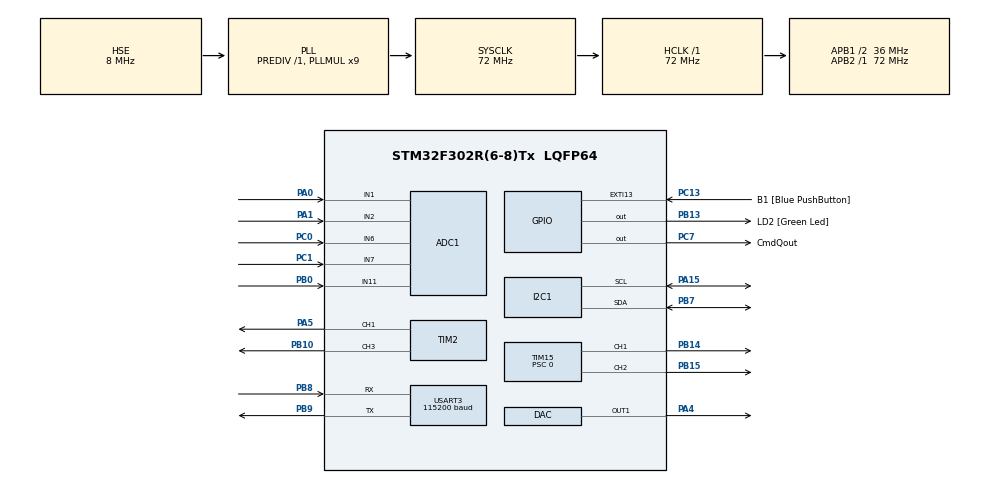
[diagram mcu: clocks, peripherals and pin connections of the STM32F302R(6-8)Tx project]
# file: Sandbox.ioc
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ADC1.Channel-0\#ChannelRegularConversion=ADC_CHANNEL_1
ADC1.Channel-3\#ChannelRegularConversion=ADC_CHANNEL_11
ADC1.Channel-4\#ChannelRegularConversion=ADC_CHANNEL_6
ADC1.Channel-5\#ChannelRegularConversion=ADC_CHANNEL_7
ADC1.ContinuousConvMode=ENABLE
ADC1.DMAContinuousRequests=ENABLE
ADC1.EOCSelection=ADC_EOC_SINGLE_CONV
ADC1.EnableInjectedConversion=DISABLE
ADC1.NbrOfConversion=4
ADC1.NbrOfConversionFlag=1
ADC1.Offset-0\#ChannelRegularConversion=0
ADC1.Offset-3\#ChannelRegularConversion=0
ADC1.Offset-4\#ChannelRegularConversion=0
ADC1.Offset-5\#ChannelRegularConversion=0
ADC1.OffsetNumber-0\#ChannelRegularConversion=ADC_OFFSET_NONE
ADC1.OffsetNumber-3\#ChannelRegularConversion=ADC_OFFSET_NONE
ADC1.OffsetNumber-4\#ChannelRegularConversion=ADC_OFFSET_NONE
ADC1.OffsetNumber-5\#ChannelRegularConversion=ADC_OFFSET_NONE
ADC1.Rank-0\#ChannelRegularConversion=1
ADC1.Rank-3\#ChannelRegularConversion=2
ADC1.Rank-4\#ChannelRegularConversion=3
ADC1.Rank-5\#ChannelRegularConversion=4
ADC1.SamplingTime-0\#ChannelRegularConversion=ADC_SAMPLETIME_7CYCLES_5
ADC1.SamplingTime-3\#ChannelRegularConversion=ADC_SAMPLETIME_7CYCLES_5
ADC1.SamplingTime-4\#ChannelRegularConversion=ADC_SAMPLETIME_7CYCLES_5
ADC1.SamplingTime-5\#ChannelRegularConversion=ADC_SAMPLETIME_7CYCLES_5
ADC1.SequencerNbRanks=1
ADC1.SubFamily=STM32F302x8
ADC1.master=1
DAC.DAC_Trigger=DAC_TRIGGER_NONE
Dma.ADC1.0.Direction=DMA_PERIPH_TO_MEMORY
Dma.ADC1.0.Instance=DMA1_Channel1
Dma.ADC1.0.MemDataAlignment=DMA_MDATAALIGN_WORD
Dma.ADC1.0.MemInc=DMA_MINC_ENABLE
Dma.ADC1.0.Mode=DMA_CIRCULAR
Dma.ADC1.0.PeriphDataAlignment=DMA_PDATAALIGN_HALFWORD
Dma.ADC1.0.PeriphInc=DMA_PINC_DISABLE
Dma.ADC1.0.Priority=DMA_PRIORITY_HIGH
Dma.Request0=ADC1
Dma.Request1=USART3_TX
Dma.USART3_TX.1.Direction=DMA_MEMORY_TO_PERIPH
Dma.USART3_TX.1.Instance=DMA1_Channel2
Dma.USART3_TX.1.MemDataAlignment=DMA_MDATAALIGN_BYTE
Dma.USART3_TX.1.MemInc=DMA_MINC_ENABLE
Dma.USART3_TX.1.Mode=DMA_NORMAL
Dma.USART3_TX.1.PeriphDataAlignment=DMA_PDATAALIGN_BYTE
Dma.USART3_TX.1.PeriphInc=DMA_PINC_DISABLE
Dma.USART3_TX.1.Priority=DMA_PRIORITY_LOW
Mcu.Family=STM32F3
Mcu.Name=STM32F302R(6-8)Tx
Mcu.Package=LQFP64
Mcu.UserConstants=TIM15_PERIOD_TICKS,4800;TIM2_PERIOD_TICKS,2400
NVIC.DMA1_Channel1_IRQn=true\:0\:0\:false\:false\:true\:false\:true\:true
NVIC.DMA1_Channel2_IRQn=true\:0\:0\:false\:false\:true\:false\:true\:true
NVIC.I2C1_EV_IRQn=true\:0\:0\:false\:false\:true\:true\:true\:true
NVIC.PriorityGroup=NVIC_PRIORITYGROUP_0
NVIC.USART3_IRQn=true\:0\:0\:false\:false\:true\:true\:true\:true
PA0.Mode=IN1-Single-Ended
PA0.Signal=ADC1_IN1
PA1.Mode=IN2-Single-Ended
PA1.Signal=ADC1_IN2
PA13.GPIO_Label=TMS
PA13.Mode=Serial_Wire
PA13.Signal=SYS_JTMS-SWDIO
PA14.GPIO_Label=TCK
PA14.Mode=Serial_Wire
PA14.Signal=SYS_JTCK-SWCLK
PA15.Mode=I2C
PA15.Signal=I2C1_SCL
PA2.GPIO_Label=USART_TX
PA2.GPIO_Mode=GPIO_MODE_AF_PP
PA2.GPIO_PuPd=GPIO_NOPULL
PA2.GPIO_Speed=GPIO_SPEED_FREQ_LOW
PA2.Signal=USART2_TX
PA3.GPIO_Label=USART_RX
PA3.GPIO_Mode=GPIO_MODE_AF_PP
PA3.GPIO_PuPd=GPIO_NOPULL
PA3.GPIO_Speed=GPIO_SPEED_FREQ_LOW
PA3.Signal=USART2_RX
PA4.Signal=COMP_DAC1_group
PA5.Signal=S_TIM2_CH1_ETR
PB0.Mode=IN11-Single-Ended
PB0.Signal=ADC1_IN11
PB10.Signal=S_TIM2_CH3
PB13.GPIO_Label=LD2 [Green Led]
PB13.Signal=GPIO_Output
PB14.GPIO_PuPd=GPIO_NOPULL
PB14.GPIO_Speed=GPIO_SPEED_FREQ_HIGH
PB14.Signal=S_TIM15_CH1
PB15.Signal=S_TIM15_CH2
PB3.GPIO_Label=SWO
PB3.Mode=Trace_Asynchronous_SW
PB3.Signal=SYS_JTDO-TRACESWO
PB7.Mode=I2C
PB7.Signal=I2C1_SDA
PB8.Mode=Asynchronous
PB8.Signal=USART3_RX
PB9.Mode=Asynchronous
PB9.Signal=USART3_TX
PC0.Signal=ADCx_IN6
PC1.Signal=ADCx_IN7
PC13.GPIO_Label=B1 [Blue PushButton]
PC13.GPIO_ModeDefaultEXTI=GPIO_MODE_IT_FALLING
PC13.Signal=GPXTI13
PC14\ -\ OSC32_IN.Mode=LSE-External-Oscillator
PC14\ -\ OSC32_IN.Signal=RCC_OSC32_IN
PC15\ -\ OSC32_OUT.Mode=LSE-External-Oscillator
PC15\ -\ OSC32_OUT.Signal=RCC_OSC32_OUT
PC7.GPIO_Label=CmdQout
PC7.GPIO_PuPd=GPIO_PULLDOWN
PC7.GPIO_Speed=GPIO_SPEED_FREQ_MEDIUM
PC7.Signal=GPIO_Output
PF0-OSC_IN.Mode=HSE-External-Clock-Source
PF0-OSC_IN.Signal=RCC_OSC_IN
PF1-OSC_OUT.Signal=RCC_OSC_OUT
ProjectManager.HeapSize=0x200
ProjectManager.StackSize=0x400
ProjectManager.TargetToolchain=STM32CubeIDE
RCC.AHBFreq_Value=72000000
RCC.APB1CLKDivider=RCC_HCLK_DIV2
RCC.APB1Freq_Value=36000000
RCC.APB1TimFreq_Value=72000000
RCC.APB2Freq_Value=72000000
RCC.APB2TimFreq_Value=72000000
RCC.CortexFreq_Value=72000000
RCC.HCLKFreq_Value=72000000
RCC.HSE_VALUE=8000000
RCC.HSI_VALUE=8000000
RCC.PLLM=8
RCC.PLLMUL=RCC_PLL_MUL9
RCC.PLLN=336
RCC.PLLP=RCC_PLLP_DIV4
RCC.PLLQ=7
RCC.PLLSourceVirtual=RCC_PLLSOURCE_HSE
RCC.SYSCLKFreq_VALUE=72000000
RCC.SYSCLKSourceVirtual=RCC_SYSCLKSOURCE_PLLCLK
RCC.TIM15Selection=RCC_TIM15CLK_PLLCLK
RCC.USBFreq_Value=72000000
SH.ADCx_IN6.0=ADC1_IN6,IN6-Single-Ended
SH.ADCx_IN7.0=ADC1_IN7,IN7-Single-Ended
SH.COMP_DAC1_group.0=DAC_OUT1,DAC_OUT1
SH.S_TIM15_CH1.0=TIM15_CH1,PWM Generation1 CH1
SH.S_TIM15_CH2.0=TIM15_CH2,PWM Generation2 CH2
SH.S_TIM2_CH1_ETR.0=TIM2_CH1,PWM Generation1 CH1
SH.S_TIM2_CH3.0=TIM2_CH3,PWM Generation3 CH3
TIM15.AutoReloadPreload=TIM_AUTORELOAD_PRELOAD_ENABLE
TIM15.AutomaticOutput=TIM_AUTOMATICOUTPUT_DISABLE
TIM15.Channel-PWM\ Generation1\ CH1=TIM_CHANNEL_1
TIM15.Channel-PWM\ Generation2\ CH2=TIM_CHANNEL_2
TIM15.OC1Preload_PWM=DISABLE
TIM15.OC2Preload_PWM=DISABLE
TIM15.Period=TIM15_PERIOD_TICKS
TIM15.Prescaler=0
TIM2.AutoReloadPreload=TIM_AUTORELOAD_PRELOAD_ENABLE
TIM2.Channel-PWM\ Generation1\ CH1=TIM_CHANNEL_1
TIM2.Channel-PWM\ Generation3\ CH3=TIM_CHANNEL_3
TIM2.OC1Preload_PWM=DISABLE
TIM2.OC3Preload_PWM=DISABLE
TIM2.Period=TIM2_PERIOD_TICKS
USART3.BaudRate=115200
USART3.VirtualMode-Asynchronous=VM_ASYNC
USART3.WordLength=WORDLENGTH_8B
board=NUCLEO-F302R8

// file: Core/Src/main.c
/* USER CODE BEGIN Header */
/**
  ******************************************************************************
  * @file           : main.c
  * @brief          : Main program body
  ******************************************************************************
  * @attention
  *
  * <h2><center>&copy; Copyright (c) 2021 STMicroelectronics.
  * All rights reserved.</center></h2>
  *
  * This software component is licensed by ST under BSD 3-Clause license,
  * the "License"; You may not use this file except in compliance with the
  * License. You may obtain a copy of the License at:
  *                        opensource.org/licenses/BSD-3-Clause
  *
  ******************************************************************************
  */
/* USER CODE END Header */
#include "main.h"

/* USER CODE BEGIN Includes */
#include "threads.hpp"
/* USER CODE END Includes */

ADC_HandleTypeDef hadc1;
DMA_HandleTypeDef hdma_adc1;

DAC_HandleTypeDef hdac;

I2C_HandleTypeDef hi2c1;

TIM_HandleTypeDef htim2;
TIM_HandleTypeDef htim15;

UART_HandleTypeDef huart3;
DMA_HandleTypeDef hdma_usart3_tx;

/* USER CODE BEGIN PV */

ADC_HandleTypeDef*  p_hadc1;
DMA_HandleTypeDef*  p_hdma_adc1;
DAC_HandleTypeDef*  p_hdac;
I2C_HandleTypeDef*  p_hi2c1;
TIM_HandleTypeDef*  p_htim2;
TIM_HandleTypeDef*  p_htim15;
UART_HandleTypeDef* p_huart3;
DMA_HandleTypeDef*  p_hdma_usart3_tx;

/* USER CODE END PV */

void SystemClock_Config(void);
static void MX_GPIO_Init(void);
static void MX_ADC1_Init(void);
static void MX_USART3_UART_Init(void);
static void MX_DMA_Init(void);
static void MX_DAC_Init(void);
static void MX_I2C1_Init(void);
static void MX_TIM15_Init(void);
static void MX_TIM2_Init(void);

int main(void)
{
  /* USER CODE BEGIN 1 */

  p_hadc1           = &hadc1;
  p_hdma_adc1       = &hdma_adc1;
  p_hdac            = &hdac;
  p_hi2c1           = &hi2c1;
  p_htim2           = &htim2;
  p_htim15          = &htim15;
  p_huart3          = &huart3;
  p_hdma_usart3_tx  = &hdma_usart3_tx;

  /* USER CODE END 1 */

  /* MCU Configuration--------------------------------------------------------*/

  /* Reset of all peripherals, Initializes the Flash interface and the Systick. */
  HAL_Init();

  /* Configure the system clock */
  SystemClock_Config();

  /* USER CODE BEGIN SysInit */

  // TODO: !!! DMA to be initialised before ADC and other peripherals !!! ////////
  //MX_GPIO_Init();
  //MX_USART2_UART_Init();
  //MX_DMA_Init();
  //MX_ADC1_Init();
  //MX_USART3_UART_Init();
  //MX_DAC_Init();
  //MX_I2C1_Init();
  //MX_TIM15_Init();

  HAL_NVIC_SetPriorityGrouping(NVIC_PRIORITYGROUP_4);
  // ??? TODO: !!! Comment in MX_DMA_Init() : HAL_NVIC_EnableIRQ(DMA1_Channel1_IRQn); --> No interrupt required

  /* USER CODE END SysInit */

  /* Initialize all configured peripherals */
  MX_GPIO_Init();
  MX_DMA_Init();
  MX_ADC1_Init();
  MX_USART3_UART_Init();
  MX_DAC_Init();
  MX_I2C1_Init();
  MX_TIM15_Init();
  MX_TIM2_Init();
  /* USER CODE BEGIN 2 */

  init_threads();

  /* USER CODE END 2 */

  /* Infinite loop */
  /* USER CODE BEGIN WHILE */
  int a = 0;
  int flag = 0;

  while (1)
  {
    tick_polled();

    a++;
    if(a/500000 >= 1)
    {
        if (flag != 0)
        {
            HAL_GPIO_WritePin(LD2_GPIO_Port, LD2_Pin, GPIO_PIN_RESET);
            flag = 0;
        }
        else
        {
            HAL_GPIO_WritePin(LD2_GPIO_Port, LD2_Pin, GPIO_PIN_SET);
            flag = 1;
        }
        a = 0;
    }

    /* USER CODE END WHILE */

  }
}

void SystemClock_Config(void)
{
  RCC_OscInitTypeDef RCC_OscInitStruct = {0};
  RCC_ClkInitTypeDef RCC_ClkInitStruct = {0};
  RCC_PeriphCLKInitTypeDef PeriphClkInit = {0};

  /** Initializes the RCC Oscillators according to the specified parameters
  * in the RCC_OscInitTypeDef structure.
  */
  RCC_OscInitStruct.OscillatorType = RCC_OSCILLATORTYPE_HSI|RCC_OSCILLATORTYPE_HSE;
  RCC_OscInitStruct.HSEState = RCC_HSE_BYPASS;
  RCC_OscInitStruct.HSEPredivValue = RCC_HSE_PREDIV_DIV1;
  RCC_OscInitStruct.HSIState = RCC_HSI_ON;
  RCC_OscInitStruct.HSICalibrationValue = RCC_HSICALIBRATION_DEFAULT;
  RCC_OscInitStruct.PLL.PLLState = RCC_PLL_ON;
  RCC_OscInitStruct.PLL.PLLSource = RCC_PLLSOURCE_HSE;
  RCC_OscInitStruct.PLL.PLLMUL = RCC_PLL_MUL9;
  if (HAL_RCC_OscConfig(&RCC_OscInitStruct) != HAL_OK)
  {
    Error_Handler();
  }

  /** Initializes the CPU, AHB and APB buses clocks
  */
  RCC_ClkInitStruct.ClockType = RCC_CLOCKTYPE_HCLK|RCC_CLOCKTYPE_SYSCLK
                              |RCC_CLOCKTYPE_PCLK1|RCC_CLOCKTYPE_PCLK2;
  RCC_ClkInitStruct.SYSCLKSource = RCC_SYSCLKSOURCE_PLLCLK;
  RCC_ClkInitStruct.AHBCLKDivider = RCC_SYSCLK_DIV1;
  RCC_ClkInitStruct.APB1CLKDivider = RCC_HCLK_DIV2;
  RCC_ClkInitStruct.APB2CLKDivider = RCC_HCLK_DIV1;

  if (HAL_RCC_ClockConfig(&RCC_ClkInitStruct, FLASH_LATENCY_2) != HAL_OK)
  {
    Error_Handler();
  }
  PeriphClkInit.PeriphClockSelection = RCC_PERIPHCLK_I2C1|RCC_PERIPHCLK_TIM15
                              |RCC_PERIPHCLK_ADC1;
  PeriphClkInit.I2c1ClockSelection = RCC_I2C1CLKSOURCE_HSI;
  PeriphClkInit.Tim15ClockSelection = RCC_TIM15CLK_PLLCLK;
  PeriphClkInit.Adc1ClockSelection = RCC_ADC1PLLCLK_DIV1;

  if (HAL_RCCEx_PeriphCLKConfig(&PeriphClkInit) != HAL_OK)
  {
    Error_Handler();
  }
}

static void MX_ADC1_Init(void)
{

  ADC_ChannelConfTypeDef sConfig = {0};

  /** Common config
  */
  hadc1.Instance = ADC1;
  hadc1.Init.ClockPrescaler = ADC_CLOCK_ASYNC_DIV1;
  hadc1.Init.Resolution = ADC_RESOLUTION_12B;
  hadc1.Init.ScanConvMode = ADC_SCAN_ENABLE;
  hadc1.Init.ContinuousConvMode = ENABLE;
  hadc1.Init.DiscontinuousConvMode = DISABLE;
  hadc1.Init.ExternalTrigConvEdge = ADC_EXTERNALTRIGCONVEDGE_NONE;
  hadc1.Init.ExternalTrigConv = ADC_SOFTWARE_START;
  hadc1.Init.DataAlign = ADC_DATAALIGN_RIGHT;
  hadc1.Init.NbrOfConversion = 4;
  hadc1.Init.DMAContinuousRequests = ENABLE;
  hadc1.Init.EOCSelection = ADC_EOC_SINGLE_CONV;
  hadc1.Init.LowPowerAutoWait = DISABLE;
  hadc1.Init.Overrun = ADC_OVR_DATA_OVERWRITTEN;
  //if (HAL_ADC_Init(&hadc1) != HAL_OK)
  //{
  //  Error_Handler();
  //}

  /** Configure Regular Channel
  */
  sConfig.Channel = ADC_CHANNEL_1;
  sConfig.Rank = ADC_REGULAR_RANK_1;
  sConfig.SingleDiff = ADC_SINGLE_ENDED;
  sConfig.SamplingTime = ADC_SAMPLETIME_7CYCLES_5;
  sConfig.OffsetNumber = ADC_OFFSET_NONE;
  sConfig.Offset = 0;
  //if (HAL_ADC_ConfigChannel(&hadc1, &sConfig) != HAL_OK)
  //{
  //  Error_Handler();
  //}

  /** Configure Regular Channel
  */
  sConfig.Channel = ADC_CHANNEL_11;
  sConfig.Rank = ADC_REGULAR_RANK_2;
  //if (HAL_ADC_ConfigChannel(&hadc1, &sConfig) != HAL_OK)
  //{
  //  Error_Handler();
  //}

  /** Configure Regular Channel
  */
  sConfig.Channel = ADC_CHANNEL_6;
  sConfig.Rank = ADC_REGULAR_RANK_3;
  //if (HAL_ADC_ConfigChannel(&hadc1, &sConfig) != HAL_OK)
  //{
  //  Error_Handler();
  //}

  /** Configure Regular Channel
  */
  sConfig.Channel = ADC_CHANNEL_7;
  sConfig.Rank = ADC_REGULAR_RANK_4;
  //if (HAL_ADC_ConfigChannel(&hadc1, &sConfig) != HAL_OK)
  //{
  //  Error_Handler();
  //}

}

static void MX_DAC_Init(void)
{

  DAC_ChannelConfTypeDef sConfig = {0};

  /** DAC Initialization
  */
  hdac.Instance = DAC;
  if (HAL_DAC_Init(&hdac) != HAL_OK)
  {
    Error_Handler();
  }

  /** DAC channel OUT1 config
  */
  sConfig.DAC_Trigger = DAC_TRIGGER_NONE;
  sConfig.DAC_OutputBuffer = DAC_OUTPUTBUFFER_ENABLE;
  if (HAL_DAC_ConfigChannel(&hdac, &sConfig, DAC_CHANNEL_1) != HAL_OK)
  {
    Error_Handler();
  }
  /* USER CODE BEGIN DAC_Init 2 */

  DAC1->DHR12R1 = 0;
  HAL_DAC_Start(&hdac, DAC_CHANNEL_1);
  /* USER CODE END DAC_Init 2 */

}

static void MX_I2C1_Init(void)
{

  hi2c1.Instance = I2C1;
  hi2c1.Init.Timing = 0x2000090E;
  hi2c1.Init.OwnAddress1 = 0;
  hi2c1.Init.AddressingMode = I2C_ADDRESSINGMODE_7BIT;
  hi2c1.Init.DualAddressMode = I2C_DUALADDRESS_DISABLE;
  hi2c1.Init.OwnAddress2 = 0;
  hi2c1.Init.OwnAddress2Masks = I2C_OA2_NOMASK;
  hi2c1.Init.GeneralCallMode = I2C_GENERALCALL_DISABLE;
  hi2c1.Init.NoStretchMode = I2C_NOSTRETCH_DISABLE;
  if (HAL_I2C_Init(&hi2c1) != HAL_OK)
  {
    Error_Handler();
  }

  /** Configure Analogue filter
  */
  if (HAL_I2CEx_ConfigAnalogFilter(&hi2c1, I2C_ANALOGFILTER_ENABLE) != HAL_OK)
  {
    Error_Handler();
  }

  /** Configure Digital filter
  */
  if (HAL_I2CEx_ConfigDigitalFilter(&hi2c1, 0) != HAL_OK)
  {
    Error_Handler();
  }

}

static void MX_TIM2_Init(void)
{

  TIM_MasterConfigTypeDef sMasterConfig = {0};
  TIM_OC_InitTypeDef sConfigOC = {0};

  htim2.Instance = TIM2;
  htim2.Init.Prescaler = 0;
  htim2.Init.CounterMode = TIM_COUNTERMODE_UP;
  htim2.Init.Period = TIM2_PERIOD_TICKS;
  htim2.Init.ClockDivision = TIM_CLOCKDIVISION_DIV1;
  htim2.Init.AutoReloadPreload = TIM_AUTORELOAD_PRELOAD_ENABLE;
  if (HAL_TIM_PWM_Init(&htim2) != HAL_OK)
  {
    Error_Handler();
  }
  sMasterConfig.MasterOutputTrigger = TIM_TRGO_RESET;
  sMasterConfig.MasterSlaveMode = TIM_MASTERSLAVEMODE_DISABLE;
  if (HAL_TIMEx_MasterConfigSynchronization(&htim2, &sMasterConfig) != HAL_OK)
  {
    Error_Handler();
  }
  sConfigOC.OCMode = TIM_OCMODE_PWM1;
  sConfigOC.Pulse = 0;
  sConfigOC.OCPolarity = TIM_OCPOLARITY_HIGH;
  sConfigOC.OCFastMode = TIM_OCFAST_DISABLE;
  if (HAL_TIM_PWM_ConfigChannel(&htim2, &sConfigOC, TIM_CHANNEL_1) != HAL_OK)
  {
    Error_Handler();
  }
  __HAL_TIM_DISABLE_OCxPRELOAD(&htim2, TIM_CHANNEL_1);
  if (HAL_TIM_PWM_ConfigChannel(&htim2, &sConfigOC, TIM_CHANNEL_3) != HAL_OK)
  {
    Error_Handler();
  }
  __HAL_TIM_DISABLE_OCxPRELOAD(&htim2, TIM_CHANNEL_3);
  HAL_TIM_MspPostInit(&htim2);

}

static void MX_TIM15_Init(void)
{

  TIM_MasterConfigTypeDef sMasterConfig = {0};
  TIM_OC_InitTypeDef sConfigOC = {0};
  TIM_BreakDeadTimeConfigTypeDef sBreakDeadTimeConfig = {0};

  htim15.Instance = TIM15;
  htim15.Init.Prescaler = 0;
  htim15.Init.CounterMode = TIM_COUNTERMODE_UP;
  htim15.Init.Period = TIM15_PERIOD_TICKS;
  htim15.Init.ClockDivision = TIM_CLOCKDIVISION_DIV1;
  htim15.Init.RepetitionCounter = 0;
  htim15.Init.AutoReloadPreload = TIM_AUTORELOAD_PRELOAD_ENABLE;
  if (HAL_TIM_PWM_Init(&htim15) != HAL_OK)
  {
    Error_Handler();
  }
  sMasterConfig.MasterOutputTrigger = TIM_TRGO_RESET;
  sMasterConfig.MasterSlaveMode = TIM_MASTERSLAVEMODE_DISABLE;
  if (HAL_TIMEx_MasterConfigSynchronization(&htim15, &sMasterConfig) != HAL_OK)
  {
    Error_Handler();
  }
  sConfigOC.OCMode = TIM_OCMODE_PWM1;
  sConfigOC.Pulse = 0;
  sConfigOC.OCPolarity = TIM_OCPOLARITY_HIGH;
  sConfigOC.OCNPolarity = TIM_OCNPOLARITY_HIGH;
  sConfigOC.OCFastMode = TIM_OCFAST_DISABLE;
  sConfigOC.OCIdleState = TIM_OCIDLESTATE_RESET;
  sConfigOC.OCNIdleState = TIM_OCNIDLESTATE_RESET;
  if (HAL_TIM_PWM_ConfigChannel(&htim15, &sConfigOC, TIM_CHANNEL_1) != HAL_OK)
  {
    Error_Handler();
  }
  __HAL_TIM_DISABLE_OCxPRELOAD(&htim15, TIM_CHANNEL_1);
  if (HAL_TIM_PWM_ConfigChannel(&htim15, &sConfigOC, TIM_CHANNEL_2) != HAL_OK)
  {
    Error_Handler();
  }
  __HAL_TIM_DISABLE_OCxPRELOAD(&htim15, TIM_CHANNEL_2);
  sBreakDeadTimeConfig.OffStateRunMode = TIM_OSSR_DISABLE;
  sBreakDeadTimeConfig.OffStateIDLEMode = TIM_OSSI_DISABLE;
  sBreakDeadTimeConfig.LockLevel = TIM_LOCKLEVEL_OFF;
  sBreakDeadTimeConfig.DeadTime = 0;
  sBreakDeadTimeConfig.BreakState = TIM_BREAK_DISABLE;
  sBreakDeadTimeConfig.BreakPolarity = TIM_BREAKPOLARITY_HIGH;
  sBreakDeadTimeConfig.BreakFilter = 0;
  sBreakDeadTimeConfig.AutomaticOutput = TIM_AUTOMATICOUTPUT_DISABLE;
  if (HAL_TIMEx_ConfigBreakDeadTime(&htim15, &sBreakDeadTimeConfig) != HAL_OK)
  {
    Error_Handler();
  }
  HAL_TIM_MspPostInit(&htim15);

}

static void MX_USART3_UART_Init(void)
{

  huart3.Instance = USART3;
  huart3.Init.BaudRate = 115200;
  huart3.Init.WordLength = UART_WORDLENGTH_8B;
  huart3.Init.StopBits = UART_STOPBITS_1;
  huart3.Init.Parity = UART_PARITY_NONE;
  huart3.Init.Mode = UART_MODE_TX_RX;
  huart3.Init.HwFlowCtl = UART_HWCONTROL_NONE;
  huart3.Init.OverSampling = UART_OVERSAMPLING_16;
  huart3.Init.OneBitSampling = UART_ONE_BIT_SAMPLE_DISABLE;
  huart3.AdvancedInit.AdvFeatureInit = UART_ADVFEATURE_NO_INIT;
  if (HAL_UART_Init(&huart3) != HAL_OK)
  {
    Error_Handler();
  }

}

static void MX_DMA_Init(void)
{

  /* DMA controller clock enable */
  __HAL_RCC_DMA1_CLK_ENABLE();

  /* DMA interrupt init */
  /* DMA1_Channel1_IRQn interrupt configuration */
  HAL_NVIC_SetPriority(DMA1_Channel1_IRQn, 0, 0);
  //HAL_NVIC_EnableIRQ(DMA1_Channel1_IRQn);
  /* DMA1_Channel2_IRQn interrupt configuration */
  HAL_NVIC_SetPriority(DMA1_Channel2_IRQn, 0, 0);
  HAL_NVIC_EnableIRQ(DMA1_Channel2_IRQn);

}

static void MX_GPIO_Init(void)
{
  GPIO_InitTypeDef GPIO_InitStruct = {0};

  /* GPIO Ports Clock Enable */
  __HAL_RCC_GPIOC_CLK_ENABLE();
  __HAL_RCC_GPIOF_CLK_ENABLE();
  __HAL_RCC_GPIOA_CLK_ENABLE();
  __HAL_RCC_GPIOB_CLK_ENABLE();

  /*Configure GPIO pin Output Level */
  HAL_GPIO_WritePin(LD2_GPIO_Port, LD2_Pin, GPIO_PIN_RESET);

  /*Configure GPIO pin Output Level */
  HAL_GPIO_WritePin(CmdQout_GPIO_Port, CmdQout_Pin, GPIO_PIN_RESET);

  /*Configure GPIO pin Output Level */
  HAL_GPIO_WritePin(GPIOA, EN_ACT_Pin|IN1_ACT_Pin|IN2_ACT_Pin, GPIO_PIN_RESET);

  /*Configure GPIO pin : B1_Pin */
  GPIO_InitStruct.Pin = B1_Pin;
  GPIO_InitStruct.Mode = GPIO_MODE_IT_FALLING;
  GPIO_InitStruct.Pull = GPIO_NOPULL;
  HAL_GPIO_Init(B1_GPIO_Port, &GPIO_InitStruct);

  /*Configure GPIO pins : USART_TX_Pin USART_RX_Pin */
  GPIO_InitStruct.Pin = USART_TX_Pin|USART_RX_Pin;
  GPIO_InitStruct.Mode = GPIO_MODE_AF_PP;
  GPIO_InitStruct.Pull = GPIO_NOPULL;
  GPIO_InitStruct.Speed = GPIO_SPEED_FREQ_LOW;
  GPIO_InitStruct.Alternate = GPIO_AF7_USART2;
  HAL_GPIO_Init(GPIOA, &GPIO_InitStruct);

  /*Configure GPIO pin : LD2_Pin */
  GPIO_InitStruct.Pin = LD2_Pin;
  GPIO_InitStruct.Mode = GPIO_MODE_OUTPUT_PP;
  GPIO_InitStruct.Pull = GPIO_NOPULL;
  GPIO_InitStruct.Speed = GPIO_SPEED_FREQ_LOW;
  HAL_GPIO_Init(LD2_GPIO_Port, &GPIO_InitStruct);

  /*Configure GPIO pin : CmdQout_Pin */
  GPIO_InitStruct.Pin = CmdQout_Pin;
  GPIO_InitStruct.Mode = GPIO_MODE_OUTPUT_PP;
  GPIO_InitStruct.Pull = GPIO_PULLDOWN;
  GPIO_InitStruct.Speed = GPIO_SPEED_FREQ_MEDIUM;
  HAL_GPIO_Init(CmdQout_GPIO_Port, &GPIO_InitStruct);

  /*Configure GPIO pins : EN_ACT_Pin IN1_ACT_Pin IN2_ACT_Pin */
  GPIO_InitStruct.Pin = EN_ACT_Pin|IN1_ACT_Pin|IN2_ACT_Pin;
  GPIO_InitStruct.Mode = GPIO_MODE_OUTPUT_PP;
  GPIO_InitStruct.Pull = GPIO_PULLDOWN;
  GPIO_InitStruct.Speed = GPIO_SPEED_FREQ_LOW;
  HAL_GPIO_Init(GPIOA, &GPIO_InitStruct);

}

void Error_Handler(void)
{
  __disable_irq();
  while (1)
  {
  }
}
